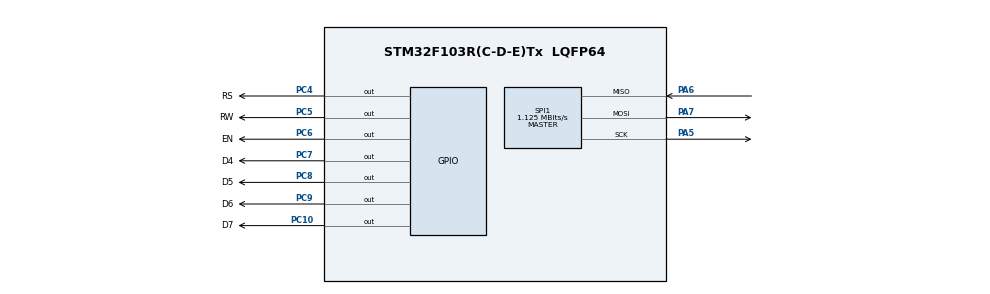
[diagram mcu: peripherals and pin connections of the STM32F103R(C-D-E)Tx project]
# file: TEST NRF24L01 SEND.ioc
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Mcu.Family=STM32F1
Mcu.Name=STM32F103R(C-D-E)Tx
Mcu.Package=LQFP64
NVIC.PriorityGroup=NVIC_PRIORITYGROUP_4
NVIC.SPI1_IRQn=true\:0\:0\:false\:false\:true
PA13.Mode=JTAG_4_pins
PA13.Signal=SYS_JTMS-SWDIO
PA14.Mode=JTAG_4_pins
PA14.Signal=SYS_JTCK-SWCLK
PA15.Mode=JTAG_4_pins
PA15.Signal=SYS_JTDI
PA5.Mode=Full_Duplex_Master
PA5.Signal=SPI1_SCK
PA6.Mode=Full_Duplex_Master
PA6.Signal=SPI1_MISO
PA7.Mode=Full_Duplex_Master
PA7.Signal=SPI1_MOSI
PB3.Mode=JTAG_4_pins
PB3.Signal=SYS_JTDO-TRACESWO
PC10.GPIO_Label=D7
PC10.GPIO_ModeDefaultOutputPP=GPIO_MODE_OUTPUT_PP
PC10.GPIO_Speed=GPIO_SPEED_FREQ_HIGH
PC10.PinState=GPIO_PIN_RESET
PC10.Signal=GPIO_Output
PC4.GPIO_Label=RS
PC4.GPIO_ModeDefaultOutputPP=GPIO_MODE_OUTPUT_PP
PC4.GPIO_Speed=GPIO_SPEED_FREQ_HIGH
PC4.PinState=GPIO_PIN_RESET
PC4.Signal=GPIO_Output
PC5.GPIO_Label=RW
PC5.GPIO_ModeDefaultOutputPP=GPIO_MODE_OUTPUT_PP
PC5.GPIO_Speed=GPIO_SPEED_FREQ_HIGH
PC5.PinState=GPIO_PIN_RESET
PC5.Signal=GPIO_Output
PC6.GPIO_Label=EN
PC6.GPIO_ModeDefaultOutputPP=GPIO_MODE_OUTPUT_PP
PC6.GPIO_Speed=GPIO_SPEED_FREQ_HIGH
PC6.PinState=GPIO_PIN_RESET
PC6.Signal=GPIO_Output
PC7.GPIO_Label=D4
PC7.GPIO_ModeDefaultOutputPP=GPIO_MODE_OUTPUT_PP
PC7.GPIO_Speed=GPIO_SPEED_FREQ_HIGH
PC7.PinState=GPIO_PIN_RESET
PC7.Signal=GPIO_Output
PC8.GPIO_Label=D5
PC8.GPIO_ModeDefaultOutputPP=GPIO_MODE_OUTPUT_PP
PC8.GPIO_Speed=GPIO_SPEED_FREQ_HIGH
PC8.PinState=GPIO_PIN_RESET
PC8.Signal=GPIO_Output
PC9.GPIO_Label=D6
PC9.GPIO_ModeDefaultOutputPP=GPIO_MODE_OUTPUT_PP
PC9.GPIO_Speed=GPIO_SPEED_FREQ_HIGH
PC9.PinState=GPIO_PIN_RESET
PC9.Signal=GPIO_Output
PD0-OSC_IN.Mode=HSE-External-Oscillator
PD0-OSC_IN.Signal=RCC_OSC_IN
PD1-OSC_OUT.Mode=HSE-External-Oscillator
PD1-OSC_OUT.Signal=RCC_OSC_OUT
ProjectManager.HeapSize=0x200
ProjectManager.StackSize=0x400
ProjectManager.TargetToolchain=MDK-ARM V5
RCC.AHBFreq_Value=72000000
RCC.APB1CLKDivider=RCC_HCLK_DIV2
RCC.APB1Freq_Value=36000000
RCC.APB1TimFreq_Value=72000000
RCC.APB2Freq_Value=72000000
RCC.APB2TimFreq_Value=72000000
RCC.HCLKFreq_Value=72000000
RCC.PLLMUL=RCC_PLL_MUL9
RCC.PLLSourceVirtual=RCC_PLLSOURCE_HSE
RCC.SYSCLKFreq_VALUE=72000000
RCC.SYSCLKSource=RCC_SYSCLKSOURCE_PLLCLK
RCC.USBFreq_Value=72000000
SPI1.BaudRatePrescaler=SPI_BAUDRATEPRESCALER_64
SPI1.CalculateBaudRate=1.125 MBits/s
SPI1.Direction=SPI_DIRECTION_2LINES
SPI1.Mode=SPI_MODE_MASTER
SPI1.VirtualType=VM_MASTER
board=TEST NRF24L01 SEND

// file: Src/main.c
#include "main.h"
#include "stm32f1xx_hal.h"
#include "nrf24l01.h"
uint8_t add[]={0x68,0x31,0x08,0x10,0x01};
uint8_t RX_BUFFER[32];
uint8_t TX_BUFFER[32]="Chu Tien Thinh";

SPI_HandleTypeDef hspi1;

void SystemClock_Config(void);
static void MX_GPIO_Init(void);
static void MX_SPI1_Init(void);

int main(void)
{

	nrf24L01_Dev dev1 =
	    {
				NRF_DATA_RATE_1MBPS,
				NRF_TX_PWR_M18dBm,
				NRF_CRC_WIDTH_1B,
				NRF_ADDR_WIDTH_3,
				NRF_STATE_TX,
				32,
				15,
				0,
				1, //busy flag
				RX_BUFFER, //rx
				TX_BUFFER, //tx
				10, //rf chanel
				add,
				add,
				&hspi1,
				GPIOA,
				GPIO_PIN_11,
				GPIOA,
				GPIO_PIN_4,
	    };

  HAL_Init();

  SystemClock_Config();

  MX_GPIO_Init();
  MX_SPI1_Init();
  NRF_Init(&dev1);

  while (1)
  {
  NRF_SendPacket(&dev1,TX_BUFFER);
	HAL_Delay(100);

  }

}

/** System Clock Configuration
*/
void SystemClock_Config(void)
{

  RCC_OscInitTypeDef RCC_OscInitStruct;
  RCC_ClkInitTypeDef RCC_ClkInitStruct;

    /**Initializes the CPU, AHB and APB busses clocks
    */
  RCC_OscInitStruct.OscillatorType = RCC_OSCILLATORTYPE_HSE;
  RCC_OscInitStruct.HSEState = RCC_HSE_ON;
  RCC_OscInitStruct.HSEPredivValue = RCC_HSE_PREDIV_DIV1;
  RCC_OscInitStruct.HSIState = RCC_HSI_ON;
  RCC_OscInitStruct.PLL.PLLState = RCC_PLL_ON;
  RCC_OscInitStruct.PLL.PLLSource = RCC_PLLSOURCE_HSE;
  RCC_OscInitStruct.PLL.PLLMUL = RCC_PLL_MUL8;
  if (HAL_RCC_OscConfig(&RCC_OscInitStruct) != HAL_OK)
  {
    _Error_Handler(__FILE__, __LINE__);
  }

    /**Initializes the CPU, AHB and APB busses clocks
    */
  RCC_ClkInitStruct.ClockType = RCC_CLOCKTYPE_HCLK|RCC_CLOCKTYPE_SYSCLK
                              |RCC_CLOCKTYPE_PCLK1|RCC_CLOCKTYPE_PCLK2;
  RCC_ClkInitStruct.SYSCLKSource = RCC_SYSCLKSOURCE_PLLCLK;
  RCC_ClkInitStruct.AHBCLKDivider = RCC_SYSCLK_DIV1;
  RCC_ClkInitStruct.APB1CLKDivider = RCC_HCLK_DIV2;
  RCC_ClkInitStruct.APB2CLKDivider = RCC_HCLK_DIV1;

  if (HAL_RCC_ClockConfig(&RCC_ClkInitStruct, FLASH_LATENCY_2) != HAL_OK)
  {
    _Error_Handler(__FILE__, __LINE__);
  }

    /**Configure the Systick interrupt time
    */
  HAL_SYSTICK_Config(HAL_RCC_GetHCLKFreq()/1000);

    /**Configure the Systick
    */
  HAL_SYSTICK_CLKSourceConfig(SYSTICK_CLKSOURCE_HCLK);

  /* SysTick_IRQn interrupt configuration */
  HAL_NVIC_SetPriority(SysTick_IRQn, 0, 0);
}

/* SPI1 init function */
static void MX_SPI1_Init(void)
{

  hspi1.Instance = SPI1;
  hspi1.Init.Mode = SPI_MODE_MASTER;
  hspi1.Init.Direction = SPI_DIRECTION_2LINES;
  hspi1.Init.DataSize = SPI_DATASIZE_8BIT;
  hspi1.Init.CLKPolarity = SPI_POLARITY_LOW;
  hspi1.Init.CLKPhase = SPI_PHASE_1EDGE;
  hspi1.Init.NSS = SPI_NSS_SOFT;
  hspi1.Init.BaudRatePrescaler = SPI_BAUDRATEPRESCALER_64;
  hspi1.Init.FirstBit = SPI_FIRSTBIT_MSB;
  hspi1.Init.TIMode = SPI_TIMODE_DISABLE;
  hspi1.Init.CRCCalculation = SPI_CRCCALCULATION_DISABLE;
  hspi1.Init.CRCPolynomial = 10;
  if (HAL_SPI_Init(&hspi1) != HAL_OK)
  {
    _Error_Handler(__FILE__, __LINE__);
  }

}

/** Configure pins as
        * Analog
        * Input
        * Output
        * EVENT_OUT
        * EXTI
*/
static void MX_GPIO_Init(void)
{

  GPIO_InitTypeDef GPIO_InitStruct;

  /* GPIO Ports Clock Enable */
  __HAL_RCC_GPIOD_CLK_ENABLE();
  __HAL_RCC_GPIOA_CLK_ENABLE();
  __HAL_RCC_GPIOC_CLK_ENABLE();
  __HAL_RCC_GPIOB_CLK_ENABLE();

  /*Configure GPIO pin Output Level */
  HAL_GPIO_WritePin(GPIOC, RS_Pin|RW_Pin|EN_Pin|D4_Pin
                          |D5_Pin|D6_Pin|D7_Pin, GPIO_PIN_RESET);

  /*Configure GPIO pins : RS_Pin RW_Pin EN_Pin D4_Pin
                           D5_Pin D6_Pin D7_Pin */
  GPIO_InitStruct.Pin = RS_Pin|RW_Pin|EN_Pin|D4_Pin
                          |D5_Pin|D6_Pin|D7_Pin;
  GPIO_InitStruct.Mode = GPIO_MODE_OUTPUT_PP;
  GPIO_InitStruct.Speed = GPIO_SPEED_FREQ_HIGH;
  HAL_GPIO_Init(GPIOC, &GPIO_InitStruct);

}

void _Error_Handler(char * file, int line)
{
  while(1)
  {
  }
}

/************************ (C) COPYRIGHT STMicroelectronics *****END OF FILE****/
